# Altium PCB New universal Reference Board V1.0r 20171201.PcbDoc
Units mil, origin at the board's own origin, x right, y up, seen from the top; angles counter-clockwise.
Board outline 2509.05 x 980.62 mil, 4 copper layers (Top Layer, L2, L3, Bottom Layer), stack 24.2 mil thick; 38 components, 48 nets, 220 pads, 284 vias.

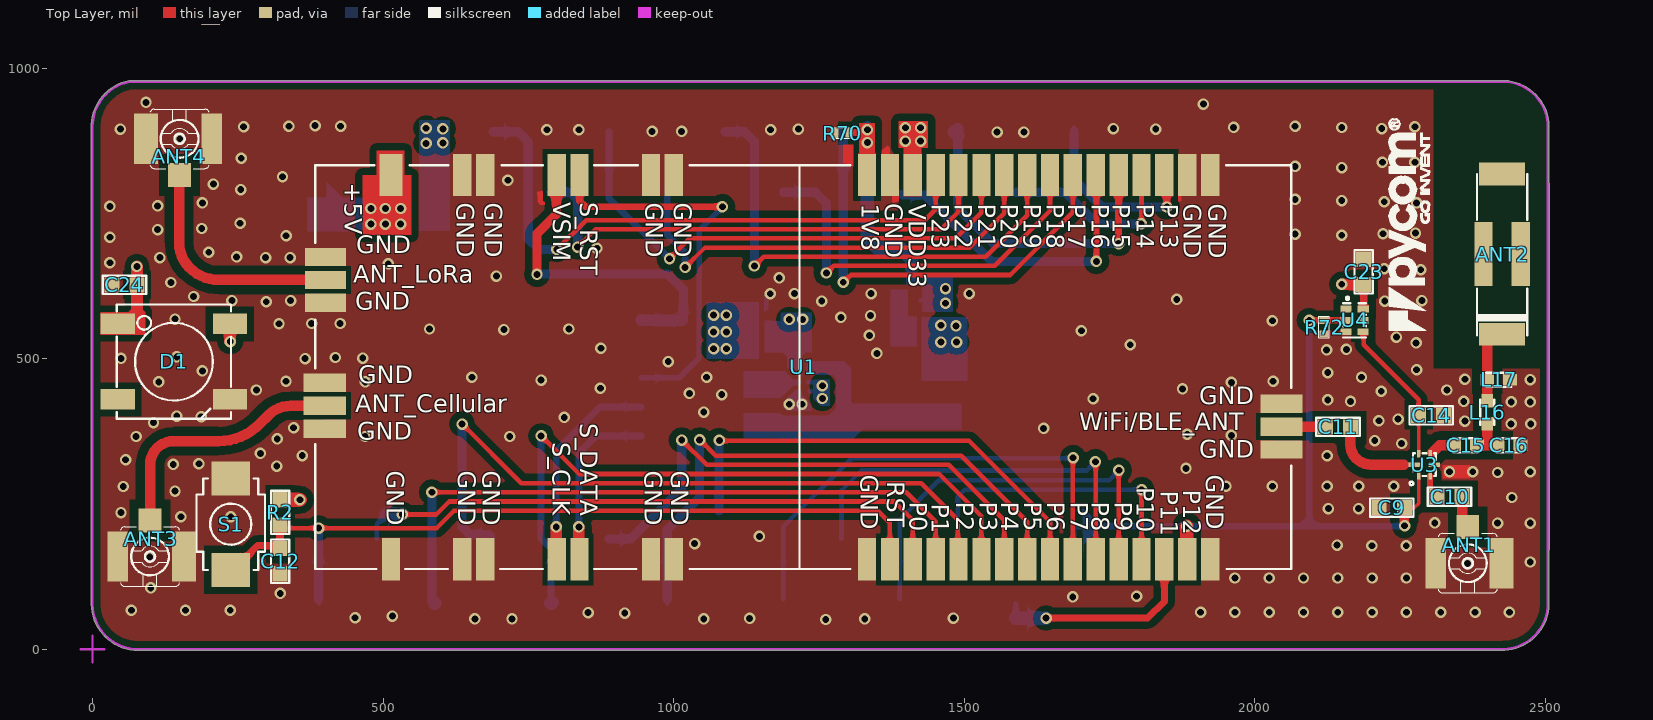
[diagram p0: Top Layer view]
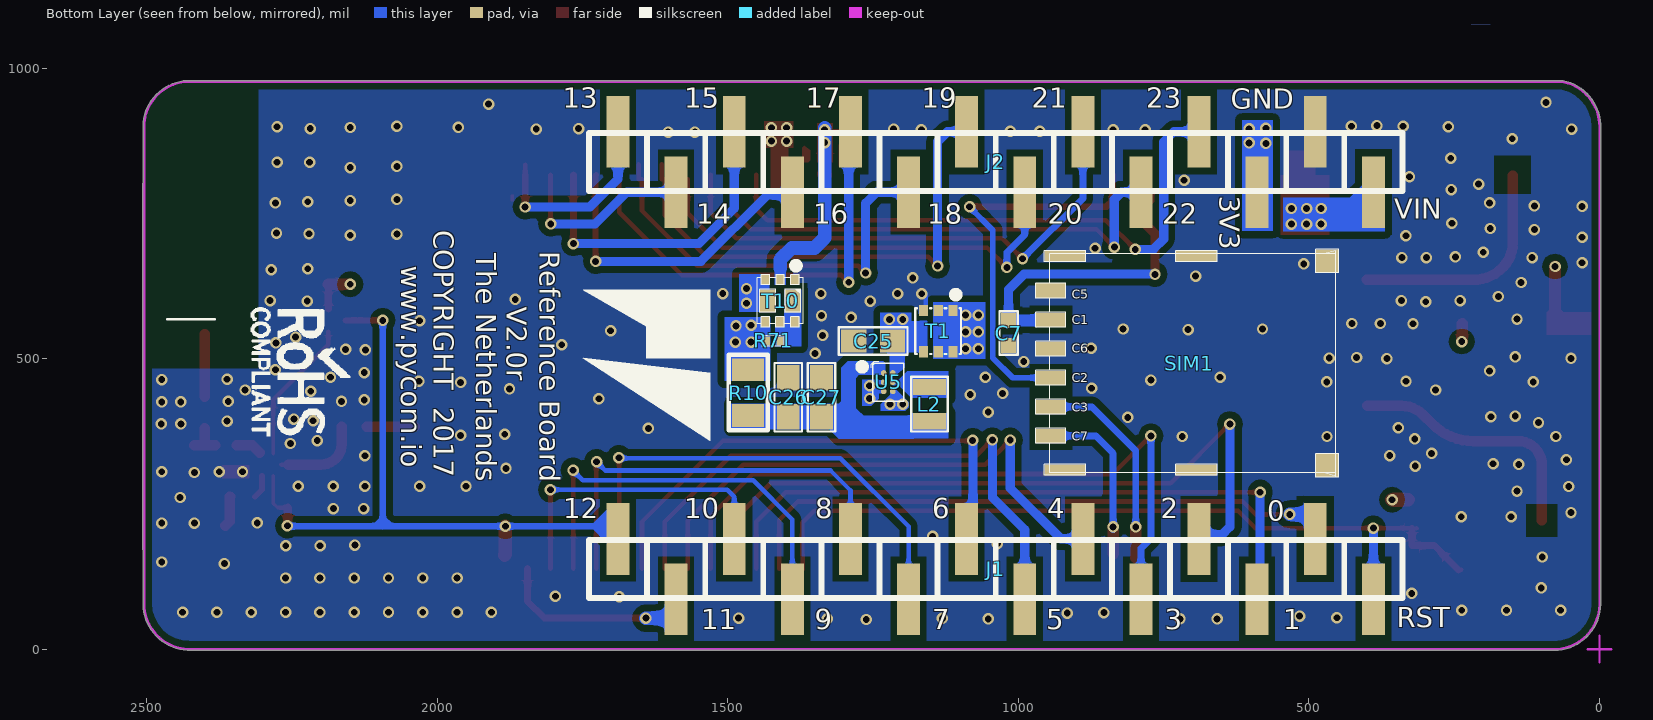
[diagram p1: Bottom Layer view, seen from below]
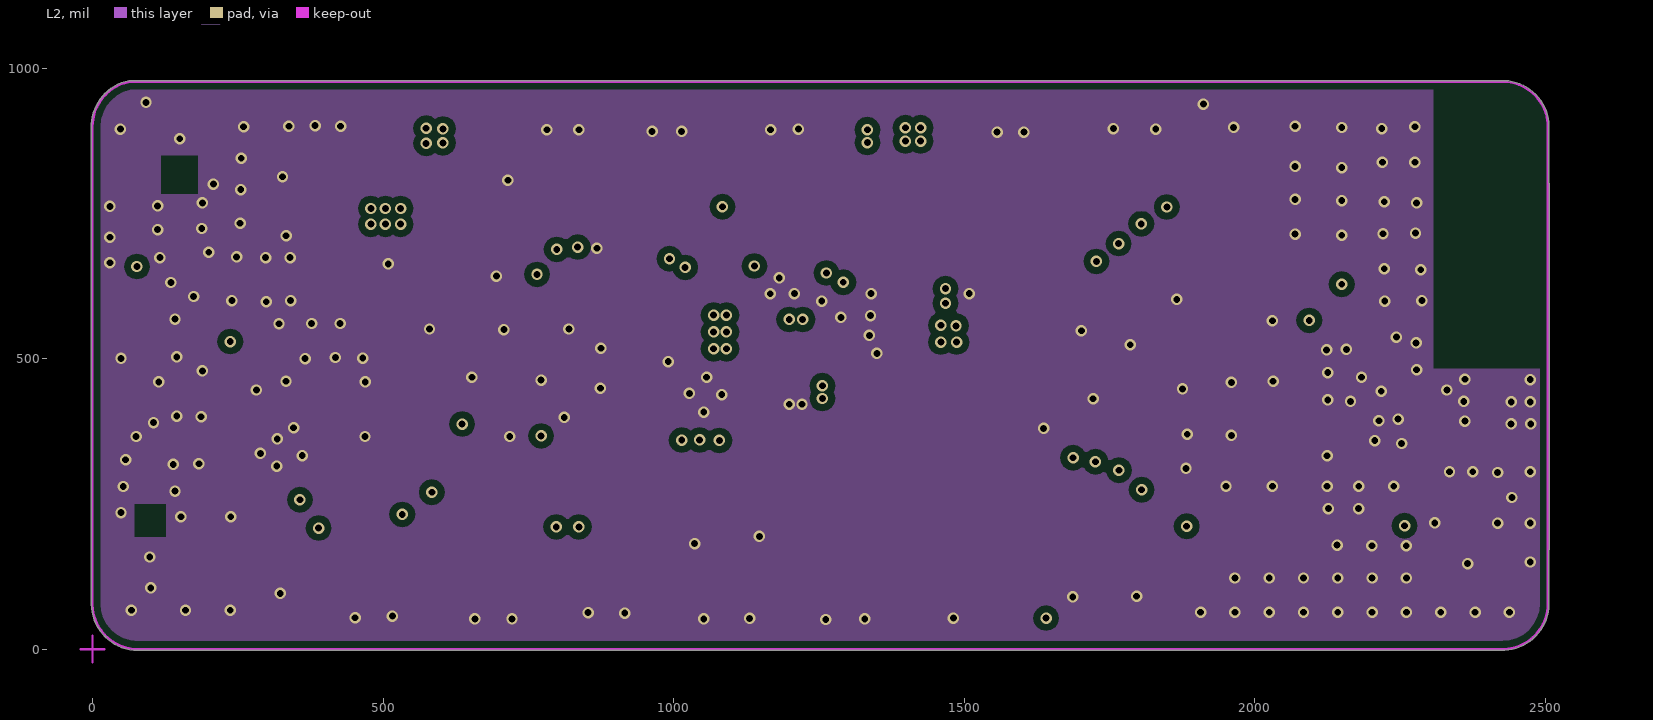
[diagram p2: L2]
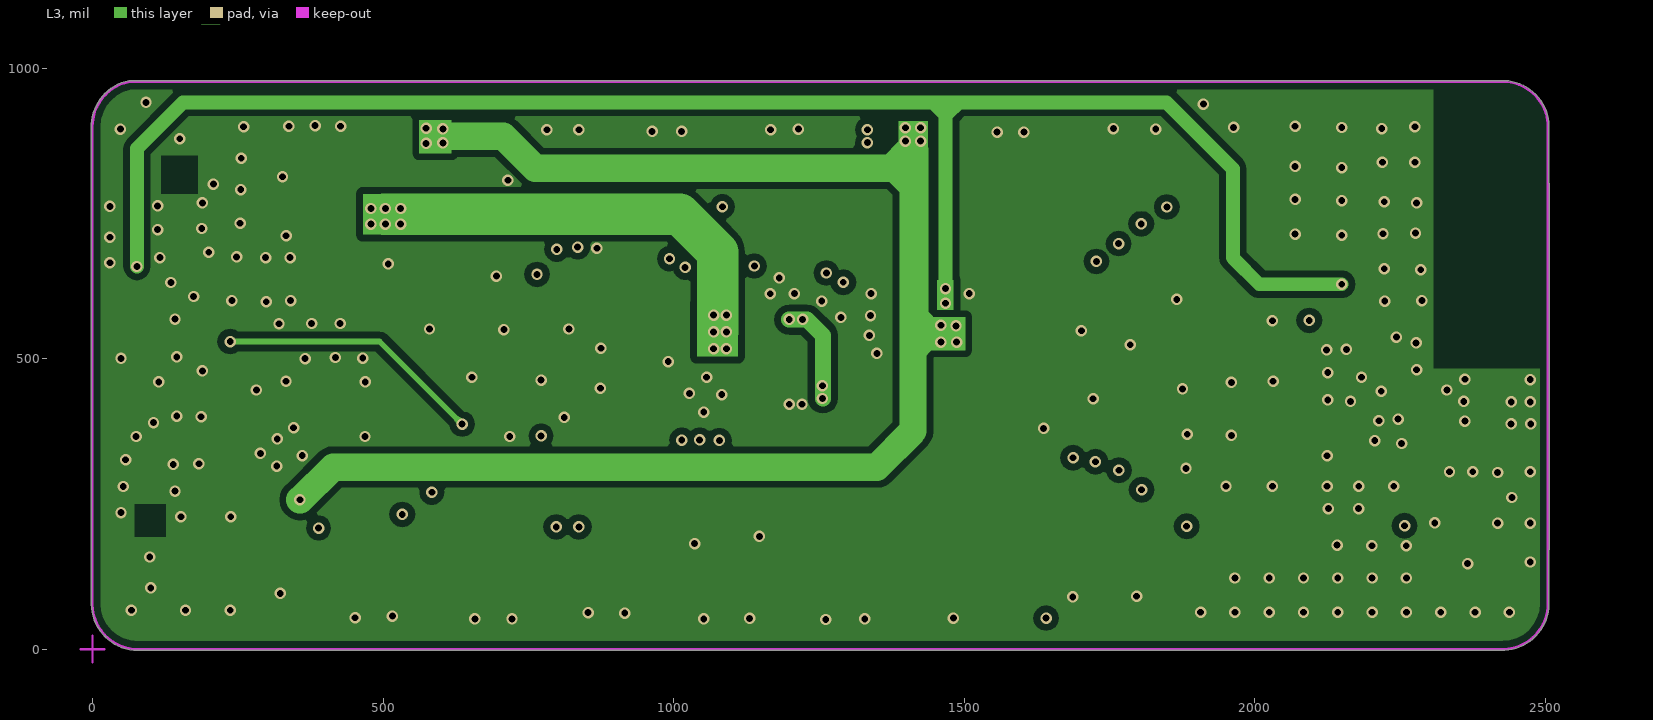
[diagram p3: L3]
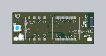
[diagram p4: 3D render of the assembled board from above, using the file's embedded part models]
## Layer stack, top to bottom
Top Solder: solder mask 0.4, Solder Resist, Dk 3.5
Top Layer: signal copper 0.7
Dielectric1: prepreg 5, FR-4, Dk 4.2
L2: signal copper 1.4
Dielectric2: core 10, FR-4, Dk 4.2
L3: signal copper 1.4
Dielectric3: prepreg 5, FR-4, Dk 4.2
Bottom Layer: signal copper 0.7
Bottom Solder: solder mask 0.4, Solder Resist, Dk 3.5

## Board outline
-1.98,170.5 cw(c-0.28,171.52) -2.27,171.52 -2.27,801.45 cw(c-0.28,801.45) -1.98,802.46 -1.98,898.44 cw(c78.74,899.16) -1.98,899.88 -1.98,902.45 cw(c0,902.45) -1.89,903.04 cw(c78.74,899.16) 62.75,978.29 cw(c63.61,976.5) 63.61,978.48 2425.1,978.48 cw(c2425.75,976.61) 2425.73,978.59 cw(c2426.46,897.87) 2429.32,978.55 cw(c2429.75,976.61) 2430.34,978.5 cw(c2426.46,897.87) 2506.66,907.02 cw(c2504.76,906.45) 2506.75,906.45 2506.75,801.82 cw(c2504.8,801.45) 2506.78,801.45 2506.78,171.52 cw(c2504.8,171.52) 2506.75,171.14 2506.75,79.41 ccw(c2426.03,78.69) 2506.75,79.42 2506.75,79.41 cw(c2426.03,78.69) 2506.75,78.69 cw(c2426.03,78.69) 2506.75,77.97 2506.75,77.45 cw(c2504.76,77.45) 2506.74,77.26 cw(c2426.03,78.69) 2430.25,-1.92 cw(c2429.75,0) 2429.75,-1.98 2428.77,-1.98 cw(c2426.03,78.69) 2427.05,-2.02 cw(c2427.03,-0.04) 2426.63,-1.98 71.66,-1.98 cw(c71.66,0) 71.13,-1.91 cw(c78.73,78.45) -1.98,77.43 cw(c0,77.45) -1.98,77.45

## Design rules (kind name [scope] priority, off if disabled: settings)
Clearance U1 [InComponent('U1')] p1: gap=7.87
Clearance U5 [InComponent('U5')] p2: gap=5
Clearance U3 [InComponent('U3')] p3: gap=5
Clearance LoRa [InPoly vs InNetClass('LoRa')] p4: gap=15
Clearance Polygon [InPolygon] p5: gap=11.81
Clearance [All] p6: gap=7.87
ComponentClearance [All] p1 off: gap=0 collisioncheckmode=3 verticalgap=0 showdistances=FALSE
FabricationTestPointUsage TestPointUsage [All] p1: valid=0 allowmultiple=FALSE
FabricationTestpoint Testpoint [(IsPad And (OnTopLayer Or OnBottomLayer))] p1: side=3 testpointundercomponent=TRUE minsize=40 maxsize=100 preferedsize=60 minholesize=0 maxholesize=40 preferedholesize=32 testpointgrid=1 allowsidetop=TRUE allowsidebottom=TRUE usegrid=TRUE gridtolerance=0.01
HoleToHoleClearance [All] p1: gap=11.81 allowstackedmicrovias=TRUE
PolygonConnect [All] p1: connectstyle=Direct reliefconductorwidth=10 reliefentries=4 polygonreliefangle="90 Angle" airgapwidth=10
RoutingVias [All] p1: holewidth=7.87 width=15.75 viastyle="Through Hole" minholewidth=5.91 minwidth=11.81 maxholewidth=59.06 maxwidth=78.74
SilkToSolderMaskClearance [IsPad] p1: minsilkscreentomaskgap=0 clearancetoexposedcopper=TRUE
SolderMaskExpansion [All] p1: expansion=4
Width [All] p1: maxlimit=118.11 minlimit=5.98 preferedwidth=10
25 further rules are at their usual default settings.

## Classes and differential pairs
component class "New universal Reference Board V1.0r 20171027": ANT1 ANT2 ANT3 ANT4 C7 C9 C10 C11 C12 C14 C15 C16 C23 C24 C25 C26 C27 D1 J1 J2 L2 L16 L17 R2 R10 R70 R71 R72 S1 SIM1 T1 T10 U1 U3 U4 U5
net class LoRa: NetANT1_1 NetANT2_1 NetANT3_1 NetANT4_1 NetC10_1 NetC11_1 NetC11_2 NetC15_1 NetC15_2

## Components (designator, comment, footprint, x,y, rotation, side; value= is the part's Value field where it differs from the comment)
ANT1 "ANT-SOCKET" ANT-SOCKET#1 2367.01,147.9 r0 top
ANT2 "ANT2450AT43B100" ANT-2450AT43B100 2426.06,679.79 r90 top locked
ANT3 "ANT-SOCKET" ANT-SOCKET#1 98.98,159.44 r0 top
ANT4 "ANT-SOCKET" ANT-SOCKET#2 148.43,847.43 r180 top
C7 "100nF_0402" 0402C#1 1017,544 r180 bottom
C9 "33pF_0402" 0402C#2 2236.12,243.44 r180 top
C10 "10pF_0402" 0402C#2 2335.51,262.47 r0 top
C11 "10pF_0402" 0402C#2 2143.4,382.45 r0 top
C12 "100nF_0402" 0402C#2 323.01,151.42 r270 top
C14 "33pF_0402" 0402C#2 2304.01,402.23 r0 top
C15 "10pF_0402" 0402CS 2363.07,350.66 r0 top
C16 "1.8pF_0402" 0402CS 2437.87,350.66 r180 top
C23 "100nF_0402" 0402C#2 2187.75,649.45 r90 top locked
C24 "100nF_0402" 0402C#2 54.96,627.05 r180 top
C25 "2.2UF_0603" 0603C 1250.12,530.44 r0 bottom
C26 "10uF_0603" 0603C 1396.12,433.58 r90 bottom locked
C27 "1uF_0603" 0603C 1339.12,433.58 r90 bottom
D1 "WS2812B" WS2812B 140.07,494.75 r0 top locked
J1 "CON14" SYMHC101-14GA40 1039.12,137.9 r0 bottom locked
J2 "CON14" SYMHC101-14GA40 1039.12,838.45 r180 bottom locked
L2 "0.47uH_0805" 0805L 1153.12,421.77 r270 bottom
L16 "2.2nH_0402" 0402CS 2400.47,407.74 r90 top
L17 "2.7pF_0402" 0402CS 2420.12,463.44 r180 top
R2 "20K_0402" 0402R 323.01,235.45 r270 top
R10 "0R_0805" 0805 1465.12,442.44 r270 bottom
R70 "220K_0201" 0201 1290,888 r0 top
R71 "220K_0201" 0201 1422.12,530.44 r0 bottom
R72 "220K_0201" 0201 2119.8,554.42 r90 top
S1 "TS-1185" SW-TS-1185 237.91,215.09 r90 top
SIM1 "693043020611_WUERTH" SIM_FiPy 706.33,492.23 r90 bottom locked
T1 "DMP2066UFDE" U-DFN2020-6 1138.12,547.44 r270 bottom
T10 "DMC1030UFDB" "U-DFN2020-6 TYPE B" 1410.12,599.44 r270 bottom
U1 "GPY_OEM" NEW_OEM_FootPrint 1223.12,485.4 r0 top locked
U3 "IC-SKY13350-385LF" MLPD-6 2292.2,317.59 r90 top locked
U4 "IC-SN74AUP1G04DRY" R-PUSON-N6(DRY) 2172.16,565.9 r180 top locked
U5 "IC-LM3281" DSBGA6(YFQ) 1224.12,459.44 r180 bottom
? "" LOGO4 2256.29,720.59 r90 top
? "" LOGO3 1614,491 r270 bottom

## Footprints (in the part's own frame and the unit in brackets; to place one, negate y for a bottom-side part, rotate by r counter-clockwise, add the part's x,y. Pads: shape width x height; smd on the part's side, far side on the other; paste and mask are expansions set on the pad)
0201 [mm]
  rect 0.3x0.4 smd: 1(-0.294,0.001) 2(0.293,0.002)
  silkscreen extent -0.47,-0.23 0.48,0.23
0402C#1 [mm]
  rect 0.66x0.66 smd mask+0.03: 1(0,0.55) 2(0,-0.55)
  silkscreen extent -0.4,-0.95 0.4,0.95
0402C#2 [mm]
  rect 0.66x0.66 smd mask+0.03: 1(-0.55,0) 2(0.55,0)
  silkscreen extent -0.95,-0.4 0.95,0.4, body extent -0.61,-0.25 0.59,0.26, height 0.51
0402CS [mm]
  rect 0.6x0.5 smd mask+0.05: 1(-0.5,0) 2(0.5,0)
  silkscreen extent -0.55,-0.31 0.55,0.31, body extent -0.61,-0.26 0.59,0.25, height 0.51
0402R [mm]
  rect 0.66x0.66 smd mask+0.03: 1(-0.55,0) 2(0.55,0)
  silkscreen extent -0.95,-0.4 0.95,0.4, body extent -0.5,-0.25 0.5,0.25, height 0.35
0603C [mm]
  rect 1.1x1 smd mask+0.05: 1(-0.85,0) 2(0.85,0.004)
  silkscreen extent -1.5,-0.6 1.5,0.6, body extent -0.78,-0.4 0.82,0.41, height 0.81
0805 [mm]
  rect 1x1.4 smd: 1(-0.975,0) 2(1.025,0)
  silkscreen extent -1.63,-0.85 1.67,0.85
0805L [mm]
  rect 0.7x1.45 smd mask+0.05: 1(-0.75,0) 2(0.75,0)
  silkscreen extent -1.2,-0.8 1.2,0.8, body extent -1,-0.64 1,0.64, height 1.27
ANT-2450AT43B100 [mm]
  rect 1x2 smd mask+0.05: 1(-3.5,0) 2(3.5,0)
  rect 2.8x0.8 smd mask+0.05: 3(0,-0.815) 4(0,0.815)
  silkscreen extent -3.55,-1.1 3.5,1.1, body extent -3.53,-1.14 3.55,1.13, height 2.1
ANT-SOCKET#1 [mm]
  rect 1x1.05 smd mask+0.05: 1(0,1.575)
  rect 0.9x2.2 smd mask+0.05: 2(-1.405,0)
  rect 1.05x2.2 smd mask+0.05: 3(1.475,0)
  silkscreen extent -1.29,-1.3 1.29,1.3, body extent -1.51,-1.32 1.49,1.53, height 1.27
ANT-SOCKET#2 [mm]
  rect 1x1.05 smd mask+0.05: 1(-0.035,0.788)
  rect 0.9x2.2 smd mask+0.05: 2(-1.44,-0.787)
  rect 1.05x2.2 smd mask+0.05: 3(1.44,-0.787)
  silkscreen extent -1.33,-2.09 1.26,0.51
DSBGA6(YFQ) [mm]
  round 0.25 smd mask+0.03: A1(-0.2,0.4) A2(0.2,0.4) B1(-0.2,0) B2(0.2,0) C1(-0.2,-0.4) C2(0.2,-0.4)
  silkscreen extent -0.74,-0.83 0.68,0.89, body extent -0.6,-0.74 0.6,0.74, height 0.4
LOGO3 [mil]
  silkscreen extent -127,-135 133,83
LOGO4 [mil]
  silkscreen extent -172,-46 193,25
MLPD-6 [mm]
  rect 0.33x0.15 smd mask+0.05: 1(-0.485,0.25) 2(-0.485,-0.25) 4(0.485,-0.25) 5(0.485,0.25)
  rect 0.2x0.51 smd mask+0.05: 3(0,-0.43) 6(0,0.43)
  silkscreen extent -0.9,-0.5 0.5,0.64, body extent -0.5,-0.51 0.51,0.51, height 0.5
NEW_OEM_FootPrint [mm]
  rect 1.85x0.8 smd mask+0.051: 24(20.911,-1.603) 25(20.911,-2.603) 26(20.911,-3.603) 27(-20.911,-0.689) 28(-20.911,-1.689) 29(-20.911,-2.689)
  rect 1.8x0.8 smd mask+0.05: 30(-20.886,4.811) 31(-20.886,3.811) 32(-20.886,2.811)
  rect 0.8x1.85 smd mask+0.051: L1(2.791,-8.401) L2(3.791,-8.401) L3(4.791,-8.401) L4(5.791,-8.401) L5(6.791,-8.401) L6(7.791,-8.401) L7(8.791,-8.401) L8(9.791,-8.401) L9(10.791,-8.401) L10(11.791,-8.401) L11(12.791,-8.401) L12(13.791,-8.401) L13(14.791,-8.401) L14(15.791,-8.401) L15(16.791,-8.401) L16(17.791,-8.401) L17(-5.654,-8.401) L18(-6.654,-8.401) L19(-9.776,-8.401) L20(-10.776,-8.401) L21(-13.898,-8.401) L22(-14.898,-8.401) L23(-18.02,-8.401) R1(2.791,8.402) R2(3.791,8.402) R3(4.791,8.402) R4(5.791,8.402) R5(6.791,8.402) R6(7.791,8.402) R7(8.791,8.402) R8(9.791,8.402) R9(10.791,8.402) R10(11.791,8.402) R11(12.791,8.402) R12(13.791,8.402) R13(14.791,8.402) R14(15.791,8.402) R15(16.791,8.402) R16(17.791,8.402) R17(-5.654,8.402) R18(-6.654,8.402) R19(-9.776,8.402) R20(-10.776,8.402) R21(-13.898,8.402) R22(-14.898,8.402)
  rect 1x1.85 smd mask+0.051: R23(-18.02,8.402)
  silkscreen extent -21.34,-8.83 21.34,8.83
R-PUSON-N6(DRY) [mm]
  rect 0.49x0.3 smd mask+0.05: 1(0.38,-0.5) 2(0.38,0) 3(0.38,0.5) 4(-0.37,0.5) 5(-0.37,0)
  rect 0.52x0.3 smd mask+0.05: 6(-0.38,-0.5)
  silkscreen extent -0.5,-1.03 0.5,0.75, body extent -0.5,-0.75 0.5,0.75, height 0.6
SIM_FiPy [mm]
  rect 0.48x1.8 smd mask+0.025: 0(-4.665,-0.325) 0(-4.665,5.425) 0(4.665,-0.325) 0(4.665,5.425)
  rect 1.03x1 smd mask+0.025: 0(-4.47,-6.045) 0(4.46,-6.045)
  rect 0.65x1.3 smd mask+0.025: C1(1.9,6.045) C2(-0.64,6.045) C3(-1.91,6.045) C5(3.17,6.045) C6(0.63,6.045) C7(-3.18,6.045)
  silkscreen extent -4.98,-6.54 4.98,6.7
SW-TS-1185 [mm]
  rect 1.5x1.7 smd: 1(-2,0) 2(2,0)
  silkscreen extent -2,-1.5 2,1.5, body extent -2.5,-1.5 2.5,1.52, height 2
SYMHC101-14GA40 [mm]
  rect 1x3.14 smd: 1(-16.51,1.32) 2(-13.97,-1.32) 3(-11.43,1.32) 4(-8.89,-1.32) 5(-6.35,1.32) 6(-3.81,-1.32) 7(-1.27,1.32) 8(1.27,-1.32) 9(3.81,1.32) 10(6.35,-1.32) 11(8.89,1.32) 12(11.43,-1.32) 13(13.97,1.32) 14(16.51,-1.32)
  silkscreen extent -17.78,-1.27 17.78,1.27
U-DFN2020-6 [mm]
  rect 0.5x0.4 smd mask+0.05: D0(-0.9,0.65) D1(-0.9,0) D2(0.9,0) D3(0.9,0.65)
  rect 0.5x0.4 smd mask+0.025: G(-0.9,-0.65) S(0.9,-0.65)
  Top Layer region: -0.45,-0.5 0.45,-0.5 0.45,-0.8 -0.45,-0.8
  Top Layer region: -0.8,0.85 0.8,0.85 0.8,-0.2 -0.8,-0.2
  silkscreen extent -1,-1 1,1, body extent -1,-1 1.02,1, height 0.63
"U-DFN2020-6 TYPE B" [mm]
  rect 1x0.7 smd mask+0.051: D1(0,0.55) D2(0,-0.55)
  rect 0.45x0.37 smd mask+0.051: D1(0.925,0.65) D2(-0.925,-0.65) G1(-0.925,0) G2(0.925,0) S1(-0.925,0.65) S2(0.925,-0.65)
  silkscreen extent -1.15,-1 1.15,1
WS2812B [mm]
  rect 1.5x0.9 smd mask+0.05: 1(-2.45,1.65) 2(-2.45,-1.65) 3(2.45,-1.65) 4(2.45,1.65)
  silkscreen extent -2.5,-2.5 2.5,2.5, body extent -2.6,-2.47 2.6,2.53, height 2.01

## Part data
C7: library part CAP-2, "SMD  Capacitor 0201"
C9 C14: library part CC0402/33PF/J%
C10 C11: library part CC0402/10PF/D%
C12 C23 C24: library part CC0402/100NF/K%16V
C15: library part CC0402/10PF/D%_S
C16 L17: library part CC0402/0,5pF/+/-0.1pF_S
C25 C26: library part CC0603/10UF/10V/K%
C27: library part CC0603/1UF/K%/10V
D1: library part DIO-WS2812B
L2: library part IND0805/0.47uH/20%
L16: library part IND0402/6.8nH/+/-0.1nH_S
R2 R10: library part RC0402/100K/F%
R70 R71 R72: library part RC0402/20K/F%
S1: library part SW-TS-1185
SIM1: library part "SIM CARD"
T1: library part FET-P-DMP2066UFDE
U1: library part LOPYOEM_Mother_Board, "LOPYOEM_Mother_Board"

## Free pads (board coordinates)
  round 35 on Bottom Overlay: 2(389.12,838.45) 3(489.12,838.45) 4(589.12,838.45) 5(689.12,838.45) 6(789.12,838.45) 7(889.12,838.45) 8(989.12,838.45) 9(1089.12,838.45) 10(1189.12,838.45) 11(1289.12,838.45) 12(1389.12,838.45) 13(1489.12,838.45) 14(1589.12,838.45) 15(1689.12,838.45) 16(389.12,136.48) 17(489.12,136.48) 18(589.12,136.48) 19(689.12,136.48) 20(789.12,136.48) 21(889.12,136.48) 22(989.12,136.48) 23(1089.12,136.48) 24(1189.12,136.48) 25(1289.12,136.48) 26(1389.12,136.29) 27(1489.12,136.48) 28(1589.12,136.48) 29(1689.12,136.48)
  round 23.62 on Top Overlay: 30(2487.14,551.25) 35(88.12,560.96)
  round 19.68 on Top Overlay: 33(20.32,593.03)
  round 11.81 on Top Overlay: 34(2270.12,285.44)

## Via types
v1: diameter 19.68, hole 11.81, Top Layer to Bottom Layer, tented both sides, 284 vias

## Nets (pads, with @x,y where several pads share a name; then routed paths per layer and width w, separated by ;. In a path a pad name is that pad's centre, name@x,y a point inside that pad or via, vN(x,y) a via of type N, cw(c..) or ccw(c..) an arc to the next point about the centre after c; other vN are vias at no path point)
+5V: J2.14 T1.D0 T1.D1 T1.D2 T1.D3 U1.R23 | length 737.7
  L3 w70.87: 502.12,748.44 1010.56,748.44 1076,683 v1@1076,546.32
  other v1: 1069,517 1091,517 1069,546 1091,546 1069,575 1091,575 479.12,731.44 504.12,731.44 530.12,731.44 479.12,758.44 504.12,758.44 530.12,758.44
DAC1(GP9): J2.10 U1.R5 | length 877.1
  Top Layer w7.87: v1(835,692) 865.69,722.69 1460.37,722.69 1490.48,752.8 U1.R5
  Bottom Layer w15.75: J2.10 822.52,786.48 835,774 v1(835,692)
DAC2(GP8): J2.9 U1.R6 | length 896.1
  Top Layer w7.87: v1(993,672) 1027.94,706.94 1485.62,706.94 1529.85,751.17 U1.R6
  Bottom Layer w11.81: J2.9 889.12,775.88 v1(993,672)
GND: ANT1.2 ANT1.3 ANT3.2 ANT3.3 ANT4.2 ANT4.3 C7.2 C9.2 C12.2 C14.2 C16.1 C23.2 C24.2 C25.2 C26.2 C27.2 D1.3 J2.13 L17.1 R70.1 R72.1 S1.2 SIM1.0 SIM1.C5 SIM1.C6 T1.G T10.S1 U1.24 U1.26 U1.27 U1.29 U1.30 U1.32 U1.L1 U1.L16 U1.L17 U1.L18 U1.L21 U1.L22 U1.L23 U1.R2 U1.R15 U1.R16 U1.R17 U1.R18 U1.R21 U1.R22 U3.3 U4.3 U5.C2
  other v1: 1262,51 658,52 722,52 1052,52 1131,53 1329,52 1481.57,53.42 452,54 516,57 853,63 916,62 1907.05,63.44 1966.11,63.44 2025.16,63.44 2084.22,63.44 2143.27,63.44 2202.33,63.44 2261.38,63.44 2320.44,63.44 2379.49,63.44 2438.55,63.44 67,67 160,67 237,67 1687,90 1797,91 323,96 100.12,105.44 1966.11,122.49 2025.16,122.49 2084.22,122.49 2143.27,122.49 2202.33,122.49 2261.38,122.49 2366.61,147.11 2474.5,150 98.58,158.65 2142,179 2202,178 2261,178 1036.29,181.79 1147.66,194 2418.37,216.9 2474.5,216.9 2310.12,217.44 152,228 238,228 49,235 2127,242 2179,242 2443,261 142,272 53,280 1950.85,280.42 2030.75,280.42 2124.89,280.42 2179.39,280.42 2239.66,280.42 2418.37,304.04 2335.51,305.38 2375.58,305.38 2474.5,305.38 1882,311 317,315 139,318 183,319 57,326 361,333 2124.89,332.78 289,337 2253,354 2206.75,358.9 318,362 75,366 469,366 718,366 1960,368 1884.17,369.9 346,381 1637,380 2441.62,387.78 2475.37,387.78 105,390 2214,393 2362.12,392.44 2247,396 812,399 145,401 187,400 1052,408 1199.12,421.44 1221.12,421.44 2441.81,425.45 2474.5,425.45 2165.12,426.44 2360.12,426.44 2126,429 1722,431 1083,438 1027.23,440.21 2218,444 282,446 2331,446 874,449 1876,448 1960,459 114,460 333,461 469.32,460.03 2032,461 772,463 2362.12,464.44 2474.5,464.05 653,468 1057,468 2184,468 2126,476 189,479 2279,481 991,495 48.96,500.44 366,500 465,501 145,503 418,502 1350,509 2124,515 2158,516 875,518 1786,524 2278,527 2244,537 1337,540 1702,548 580,551 708,550 820,551 321,560 377.12,560.44 426.12,560.44 2030.75,565.22 142,568 1288,571 1339,574 299,598 1255,599 2224,599 240,600 341,600 2288,600 1866,602 174,607 1166.41,611.7 1208,612 1340,612 1509,612 135,631 1182,639 695,642 2286,653 2223.18,654.74 509,663 29.96,665.05 116,674 248,675 298,674 340,674 200,683 868,690 29.96,709 333.12,711.44 2149.96,712.27 2069.75,714.27 2221,715 2277,716 112,722 188,724 254,733 29.96,762 112,763 189,768 2279,768 2223.18,770.05 2149.96,772.05 2069.75,774.05 255,791 208.12,800.44 715,807 327,813 2149.96,828.82 2069.75,830.82 2220,838 2276,838 256,845 150.12,878.44 963,891 1014,891 1557,890 1603,890 48,895 782,894 837,894 1167,894 1215,895 1830,895 1757,896 2219,896 2149.96,897.88 260,899 1964,898 2276,899 2069.75,899.88 338,900 383,901 427,900 1912,938 92,941
GPI2(2): J1.10 U1.L11 | length 732.4
  Top Layer w7.87: v1(1726.12,322.44) 1726.7,321.85 U1.L11 U1.L11@1726.7,138.51
  Bottom Layer w7.87: J1.10 1289.12,273.12 1323.44,307.44 1711.12,307.44 v1(1726.12,322.44) 1726.12,326.44 1725.62,326.94 v1@1723.62,324.94
GPI36: J2.1 U1.R14 | length 346.1
  Top Layer w7.87: U1.R14@1848.81,808.69 U1.R14@1848.81,833.37
  Top Layer w11.81: v1@1848.81,761.74 U1.R14@1848.81,815.17
  Bottom Layer w7.87: J2.1 J2.1@1689.12,897.51
  Bottom Layer w15.75: J2.1 1689.12,809.44 1737.56,761 v1(1849,761)
GPI37: J2.2 U1.R13 | length 322.8
  Top Layer w7.87: v1(1805,732) 1805.44,732.44 U1.R13
  Bottom Layer w15.75: J2.2 1674.07,786.48 1728.56,732 v1(1805,732)
GPI38: J2.3 U1.R12 | length 568.1
  Top Layer w11.81: v1(1766,698) 1766.07,698.07 U1.R12
  Bottom Layer w10: J2.3@1489.12,883.94 J2.3
  Bottom Layer w15.75: J2.3@1489.12,883.94 1489.12,758.88 1550,698 v1(1766,698)
  Bottom Layer w19.68: J2.3@1485.12,891.45 J2.3@1489.12,895.45
  Bottom Layer w23.62: J2.3@1485.12,891.45 1483.36,889.7 J2.3@1489.12,883.94
GPI39: J2.4 U1.R11 | length 537.2
  Top Layer w10: U1.R11 1727.74,815.13 v1(1727.74,667.38)
  Bottom Layer w10: J2.4 J2.4@1394.17,781.44
  Bottom Layer w15.75: J2.4@1394.17,781.44 1432.56,781.44 1546.62,667.38 v1(1727.74,667.38)
GPIO00: D1.4 J1.4 U1.L5 | length 1711.6
  Top Layer w7.87: v1(636.12,387.44) 737.88,285.68 1426.33,285.68 1489.12,222.89 U1.L5@1489.12,173.45
  Top Layer w10: v1@236.53,530.03 v1(237.12,529.44)
  Top Layer w19.68: v1@236.53,530.03 D1.4
  L3 w10: v1(237.12,529.44) 494.12,529.44 v1(636.12,387.44)
  Bottom Layer w7.87: J1.4@682.03,196.96 J1.4 689.12,196.96 J1.4@682.03,196.96
  Bottom Layer w15.75: v1(636.12,387.44) 636.12,210.44 649.6,196.96 J1.4@682.03,196.96
GPIO02(GPIO03): J1.2 U1.L3 | length 1061.1
  Top Layer w7.87: v1(533.12,231.96) 533.29,231.78 591.47,231.78 613.87,254.19 1379.83,254.19 1411.74,222.27 U1.L3@1411.74,138.51
  Bottom Layer w7.87: J1.2 489.12,214.95 J1.2@506.13,231.96
  Bottom Layer w23.62: J1.2@506.13,231.96 v1(533.12,231.96)
GPIO04: J1.5 U1.L6 | length 1205.2
  Top Layer w7.87: v1(772,367) 837.57,301.43 1457.63,301.43 1529.85,229.21 U1.L6@1529.85,138.51
  Bottom Layer w7.87: v1(772,367) 773.86,367 v1@775,365.86 ; J1.5@790.96,80.69 J1.5@790.96,85.93
  Bottom Layer w11.81: v1@775,365.86 772,362.86 772,190.77 789.12,173.65 J1.5
  Bottom Layer w23.62: J1.5@789.12,78.85 J1.5@790.96,80.69
GPIO12(18): J1.11 U1.L12 | length 720.3
  Top Layer w7.87: U1.L12@1766.07,138.51 v1@1766.07,308.44
  Bottom Layer w7.87: J1.11 1389.12,223.12 1456.44,290.44 1750.12,290.44 1766.62,306.94 v1(1766.62,307.94)
GPIO13(19): J1.12 U1.L13 | length 536
  Top Layer w7.87: U1.L13@1805.44,138.51 U1.L13 v1@1805.44,280.44
  Bottom Layer w7.87: J1.12 1489.12,262.44 1501.12,274.44 v1(1805.62,274.44)
GPIO14(14): J2.11 U1.R4 | length 1031.2
  Top Layer w7.87: v1(799,688) 849.44,738.44 1432.12,738.44 1451.11,757.43 U1.R4
  Bottom Layer w15.75: J2.11 732.58,890.42 750,873 750,706 768,688 v1(799,688)
GPIO15: J1.6 U1.L7 | length 939.5
  Top Layer w7.87: v1(1014.08,359.82) 1014.27,359.82 1056.91,317.18 1473.99,317.18 1569.22,221.94 U1.L7@1569.22,138.51
  Bottom Layer w15.75: J1.6 926.87,189.87 1014.08,277.08 v1(1014.08,359.82)
GPIO21(6): C9.1 J1.14 R72.2 U1.L15 U3.1 U4.2 | length 1168.1
  Top Layer w6: v1@2257.77,212.78 v1(2258.12,212.44) ; C9.1 2275.12,243.44 2282.36,250.68 U3.1
  Top Layer w10: v1@2091.8,565.9 U4.2@2158.18,565.9
  Top Layer w15: v1@2257.77,212.78 C9.1
  Top Layer w23.62: v1(1883.12,211.44) 1883.12,163.18 U1.L15@1884.18,162.11
  Bottom Layer w7.87: J1.14 J1.14@1689.12,211.44 ; v1@2257.12,211.44 v1(2258.12,212.44)
  Bottom Layer w11.81: J1.14@1689.12,211.44 v1@2257.12,211.44 ; 2094.12,211.44 v1(2094.12,565.9)
GPIO22(11): J1.13 U1.L14 | length 349.4
  Top Layer w11.81: v1(1641.17,53.42) 1816.1,53.42 1844.81,82.13 U1.L14@1844.81,138.51
  Bottom Layer w7.87: J1.13@1589.12,53.42 J1.13@1589.12,78.85
  Bottom Layer w23.62: J1.13@1589.12,53.42 v1(1641.17,53.42)
GPIO32(3): J2.7 U1.R8 | length 864.3
  Top Layer w7.87: v1(1139.12,659.44) 1155.13,675.45 1537.38,675.45 1608.59,746.66 U1.R8@1608.59,808.69 ; U1.R8@1613.8,808.69 U1.R8@1613.8,834.29
  Bottom Layer w15.75: J2.7 1122.13,890.42 1139.12,873.44 v1(1139.12,659.44)
GPIO33(12): J2.8 U1.R7 | length 814
  Top Layer w7.87: v1(1020,657) 1054.19,691.19 1509.88,691.19 1569.22,750.54 U1.R7@1569.22,808.69 ; U1.R7@1574.43,808.69 U1.R7@1574.43,834.29
  Bottom Layer w11.81: J2.8 989.12,713.88 1020,683 v1(1020,657)
LORA_CLK: J1.7 U1.L8 | length 1007.4
  Top Layer w7.87: v1(1044.92,360.2) 1045.5,360.2 1072.78,332.93 1495.09,332.93 1608.59,219.42 U1.L8@1608.59,138.51
  Bottom Layer w7.87: J1.7@989.12,78.85 J1.7
  Bottom Layer w15.75: J1.7 989.12,205.4 1044.92,261.2 v1(1044.92,360.2)
LORA_MISO: J1.9 U1.L10 | length 863.6
  Top Layer w7.87: U1.L10@1687.33,138.51 U1.L10 v1@1687.33,329.44
  Bottom Layer w7.87: J1.9 1189.12,211.12 1306.44,328.44 1686.62,328.44 v1(1687.62,329.44)
LORA_MOSI: J1.8 U1.L9 | length 831.3
  Top Layer w7.87: v1(1078.83,359.23) 1079.63,358.44 1508.57,358.44 1647.96,219.05 U1.L9@1647.96,138.51
  Bottom Layer w7.87: v1@1078.26,356.34 v1@1081.85,359.94
  Bottom Layer w15.75: J1.8@1078.26,237.9 v1@1078.26,356.34
NetANT1_1: ANT1.1 C10.2 | length 53.5
  Top Layer w18: C10.2@2357.42,262.21 2357.42,219.89 ANT1.1@2365.04,212.27
  Top Layer w18.6: C10.2 C10.2@2357.42,262.21
NetANT2_1: ANT2.1 L16.2 L17.2 | length 107.7
  Top Layer w18: L16.2@2400.47,434.32 ANT2.1@2400.47,542
NetANT3_1: ANT3.1 U1.28 | length 438.4
  Top Layer w18: ANT3.1 98.98,316.97 cw(c140.03,316.97) 111,346 cw(c139.97,317.03) 139.97,358 216.58,358 ccw(c216.58,458) 287.29,387.29 303,403 cw(c341.39,364.61) 341.39,418.9 U1.28
NetANT4_1: ANT4.1 U1.31 | length 402.2
  Top Layer w18: ANT4.1@149.12,814.44 149.12,699.89 ccw(c210.57,699.89) 167.12,656.44 ccw(c217.82,707.14) 217.82,635.44 U1.31
NetC10_1: C10.1 U3.2 | length 40.9
  Top Layer w10: U3.2 2302.04,274.28 C10.1
NetC11_1: C11.1 U1.25 | length 83
  Top Layer w11.81: C11.1@2121.3,382.9 C11.1
  Top Layer w18: U1.25@2038.91,382.9 C11.1@2121.3,382.9
NetC11_2: C11.2 U3.6 | length 153.3
  Top Layer w7.87: 2256.77,317.59 U3.6@2268.58,317.59
  Top Layer w18: C11.2 2165.06,351.85 ccw(c2198.15,351.85) 2174.75,328.45 ccw(c2200.98,354.69) 2200.98,317.59 2256.77,317.59
NetC14_1: C14.1 U3.5 U4.4 | length 248.7
  Top Layer w6: U3.5 C14.1
  Top Layer w7.87: U4.4@2187.71,546.22 2187.71,523.84 2282.36,429.19 C14.1
NetC15_1: C15.1 U3.4 | length 45.9
  Top Layer w6: U3.4 U3.4@2302.04,338
  Top Layer w18: 2306,338 2318.66,350.66 C15.1 ; C15.1@2343.38,351.15 C15.1@2345.35,351.15
NetC15_2: C15.2 C16.2 L16.1 | length 65.4
  Top Layer w18: C15.2 2400.47,350.66 ; L16.1@2400.47,380.58 2400.47,350.66 ; C16.2 2400.47,350.66
NetC26_1: C26.1 C27.1 L2.2 R10.2 U5.A1 | length 443.4
  Bottom Layer w7.87: U5.A1@1235.39,475.44 1284.12,475.44 ; 1429.12,392.24 1448.28,392.24 R10.2@1458.12,402.08
  Bottom Layer w19.68: 1284.12,475.44 1289.12,470.44 1289.12,392.24
  Bottom Layer w25: L2.2@1155.92,389.44 1283.12,389.44
  Bottom Layer w27.56: L2.2 L2.2@1155.92,389.44 ; 1283.12,389.44 1285.92,392.24 1289.12,392.24 ; 1291.12,392.24 1429.12,392.24
NetR71_1: R71.1 T10.D1 T10.G2 | length 124.4
  Bottom Layer w7.87: T10.D1@1388.47,599.44 1384.53,595.5 1384.53,563.02 1384.53,538.03 1391.72,530.83 R71.1@1410.12,530.83 ; T10.G2 R71.1@1410.12,530.83 ; R71.1 R71.1@1410.12,530.83
PU(NRESET): C12.1 J1.1 R2.2 S1.1 U1.L2 | length 1420.4
  Top Layer w7.87: S1.1 S1.1@242.5,136.35 ; R2.2@314.57,208.41 321.83,207.51 322.23,207.46 R2.2@322.61,207.41 ; R2.2@322.08,208.41 v1(389.12,208.41) 592.1,208.41 622.12,238.44 1351.57,238.44 1372.37,217.64 U1.L2@1372.37,162.11 ; U1.L2@1371.16,137.58 U1.L2@1371.16,162.11
  Top Layer w11.81: S1.1@242.5,136.35 284.26,178.11 322.61,178.11 R2.2@322.61,207.41
  Bottom Layer w7.87: J1.1@389.12,78.85 J1.1
  Bottom Layer w15.75: J1.1 v1(389.12,208.41)
RF_POWER: C23.1 C24.1 D1.1 T10.D2 U4.6 | length 3057
  Top Layer w11.81: U4.6@2187.71,585.59 C23.1 C23.1
  Top Layer w19.68: v1(2149.96,628.05) 2187.5,628.05 C23.1
  Top Layer w20: D1.1 72.71,559.71 76.49,563.49 v1(76.49,658.58)
  L3 w23.62: v1(76.49,658.58) 76.49,861.81 155.62,940.94 1848.42,940.94 1962.75,826.6 1962.75,673.45 2008.15,628.05 v1(2149.96,628.05) ; v1(1468.12,620.44) 1468.12,933.44
  Bottom Layer w7.87: T10.D2@1425.77,599.44 T10.D2@1429.71,603.37
  other v1: 1468.12,595.44
SIM_CLK: SIM1.C3 U1.L20 | length 369.6
  Top Layer w11.81: v1(798.12,210.44) 798.12,203.31 v1@798.88,202.55
  Top Layer w19.68: U1.L20@798.12,157.52 v1(798.12,210.44)
  Bottom Layer w11.81: v1(798.12,210.44) 798.12,341.44 873.71,417.03 SIM1.C3
SIM_DATA: SIM1.C7 U1.L19 | length 303
  Top Layer w11.81: v1@837.12,205.44 838.25,204.31 v1@838.25,201.35
  Top Layer w19.68: U1.L19@837.12,163.72 v1(837.12,210.44)
  Bottom Layer w11.81: v1@837.12,205.44 837.12,336.87 838.25,338 837.97,338.29 866.71,367.03 SIM1.C7
SIM_RESET: SIM1.C2 U1.R19 | length 685.6
  Top Layer w11.81: U1.R19 838.25,771.31 848.12,761.44 v1(1084.12,761.44)
  Bottom Layer w10: SIM1.C2 1010.03,467.03 1044.13,501.13 1044.13,721.13 1084.12,761.12 v1(1084.12,761.44)
SW: L2.1 U5.B2 | length 60.6
  Bottom Layer w6: L2.1@1153.12,458.96 1153.59,459.44 1202.42,459.44
  Bottom Layer w7.87: 1205.23,459.63 1216.06,459.63 U5.B2
U0TXD(GPIO01): J1.3 U1.L4 | length 1161.4
  Top Layer w7.87: v1@584.98,269.3 585.62,269.93 1400.36,269.93 1451.11,219.18 U1.L4@1451.11,138.51
  Bottom Layer w7.87: J1.3@584.12,83.85 J1.3@588.96,79
  Bottom Layer w15.75: v1(584,270) 584,83.97 J1.3@584.12,83.85
  Bottom Layer w23.62: J1.3@588.96,79 J1.3@589.12,78.85
VDD1V8: R70.2 T10.G1 U1.R1 | length 422.6
  Top Layer w10: v1@1332.62,893.94 1332.62,896.07 v1@1339.69,889
  Top Layer w11.81: R70.2@1302.12,889 v1@1339.69,889
  Top Layer w23.62: U1.R1 1335.12,818.29 1333.62,819.79 v1(1333.62,871.94)
  Bottom Layer w7.87: T10.G1 1410.12,655.44
  Bottom Layer w23.62: v1@1333.62,896.94 v1(1333.62,871.94) 1333.62,707.94 1351.12,690.44 1390.12,690.44 1410.12,670.44 1410.12,655.44
  other v1: 1333.62,893.94
VDD5: C25.1 T1.S U5.A2 U5.B1 U5.C1 | length 400.4
  L3 w27.56: v1@1199.12,567 1230,567 1257.12,539.88 v1@1257.12,431.44
  Bottom Layer w7.87: 1165.12,555.44 1165.12,518.41 1164.71,518 1204.22,518 C25.1@1216.24,530.03 ; U5.A2@1216.24,478.56 C25.1@1216.24,530.03 ; C25.1 C25.1@1216.24,530.03 ; U5.B1 1252.12,459.44 1255.12,456.44 v1@1255.12,444.44 ; U5.C1@1234.24,443.69 1254.37,443.69 v1@1255.12,444.44 ; v1@1255.12,425.44 v1@1255.12,444.44
  other v1: 1256.12,431.44 1256.12,453.44 1199.12,567.44 1222.12,567.44
VDD33: J2.12 R2.1 R10.1 R71.2 T10.S2 U1.R3 | length 2622.2
  Top Layer w23.62: R2.1@329.61,257.11 329.66,257.05 v1(356.96,257.05)
  L3 w11.81: 1415.12,463.44 1415.12,542.44 ; v1(1460.12,528.44) 1474.12,542.44
  L3 w47.24: v1(356.96,257.05) 357.73,257.05 414.12,313.44 1350.12,313.44 1412.12,375.44 1412.12,881.44 ; 608.12,882.44 707.12,882.44 761.89,827.66 1411.84,827.66 1412.12,827.94 ; 1415.12,542.44 1474.12,542.44
  other v1: 1487.12,528.44 1486.12,556.44 1460.12,557.44 574.12,870.44 603.12,871.44 1399.12,874.44 1425.12,874.44 603.12,895.44 574.12,896.44 1399.12,897.44 1425.12,897.44
VDET-1(GP30): J2.6 U1.R9 | length 710.8
  Top Layer w7.87: v1(1263.12,647.44) 1275.38,659.7 1553.09,659.7 1647.96,754.57 U1.R9@1647.96,808.69 ; U1.R9@1653.17,808.69 U1.R9@1653.17,834.29
  Bottom Layer w15.75: J2.6 1244.07,786.48 1263.12,767.44 v1(1263.12,647.44)
VDET-2(GP31): J2.5 U1.R10 | length 1046.8
  Top Layer w7.87: v1(1292.12,631.44) 1304.63,643.95 1579.55,643.95 1687.33,751.73 U1.R10@1687.33,808.69 ; U1.R10@1692.54,808.69 U1.R10@1692.54,834.29
  Bottom Layer w7.87: v1@1289.12,631.44 J2.5
  Bottom Layer w15.75: J2.5 1292.12,887.42 v1(1292.12,631.44)
VSIM(SIM_VCC): C7.1 SIM1.C1 U1.R20 | length 574.6
  Top Layer w15.75: v1(765,645) 765,715 798.35,748.35 798.35,816.7 U1.R20
  Bottom Layer w15.75: v1(765,645) 765.57,645.57 990.43,645.57 1017,619 C7.1
  Bottom Layer w19.68: SIM1.C1 944.32,566 C7.1@1015,566
pads on no net: ANT2.2 ANT2.3 ANT2.4 D1.2 U4.1 U4.5

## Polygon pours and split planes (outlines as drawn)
GND on L2 "G" (solid, remove dead copper, pour order 10): -74,1046 2606,1046 2628,1024 2658,994 2658,922 2658,10 2608,-40 2570,-78 2442,-78 24,-78 -78,24
GND on Top Layer "G" (solid, remove dead copper, pour order 12): -64,1086 2554,1086 2612,1028 2642,998 2642,912 2642,20 2580,-42 2534,-88 2362,-88 -4,-88 -60,-32
GND on L3 "G" (solid, remove dead copper, pour order 14): -83,1048 2599,1048 2606,1041 2638,1009 2638,900 2638,21 2587,-30 2545,-72 2380,-72 24,-72 -60,12
GND on Bottom Layer "G" (solid, remove dead copper, pour order 16): -67,1028 2631,1028 2669,990 2700,959 2700,625 2700,56 2628,-16 2580,-64 2232,-64 -49,-64 -60,-53

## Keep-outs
Keep-Out Layer:
  lines w3.94: -20.55,0 0,0 ; -0.28,171.52 -0.28,801.45 ; 0,-22.93 0,0 ; 0,22.93 0,0 ; 0,898.45 cw(c78.74,899.16) 63.62,976.44 ; 0,902.45 0,77.45 ccw(c78.73,78.45) 71.66,0.03 ; 63.61,976.5 329.42,976.5 372.39,976.5 ; 71.66,0 313.69,0 ; 312.12,0 1985.31,0 ; 320.57,0 321.96,0 323.61,0 ; 366.28,976.5 2032.04,976.5 ; 1957.8,0 2429.75,0 ; 2016.8,976.5 2429.64,976.5 2429.75,976.61 ; 2425.75,976.61 cw(c2426.46,897.87) 2504.73,906.45 ; 2427.03,-0.04 ccw(c2426.03,78.69) 2504.76,79.4 ; 2504.76,77.45 2504.76,906.45 ; 2504.8,171.52 2504.8,801.45 ; 0,0 20.55,0 0,0
  text ".Layer_Name" at -7,1074 h78.74

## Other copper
Top Layer:
  rectangle net +5V: 464.62,712.44 548.62,816
  rectangle net GND: 2323.7,293.57 2370.94,317.19
  rectangle net VDD33: 1387.12,862.44 1438.12,909.44
  rectangle net VDD33: 1396.12,779.44 1427.12,864.44
  rectangle net VDD1V8: 1319.12,837.44 1346.62,905.94
  rectangle net +5V: 489.12,762.44 537.12,858.44
  rectangle net RF_POWER: 14,541 91,580
  region net GND: 1868.77,770.39 1868.77,782 1874,782 1874,771 1872,771
  region net GND: 1309.38,830.75 1309.38,868.38 1292,868.38 1292,837
  region net GND: 1388,770.66 1388,784 1387,785 1383,781 1376,781 1376,770 1378,768
  pour cut-out: 1388,773 1388,749 1404,749 1404,770 1406,772
  region net GND: 775.26,789.05 775.26,771.49 778,768.75 778,765 771,765 766,770 766,781 765,782 765,787
  pour cut-out: 118.31,848.91 181.3,848.91 181.3,783.95 118.31,783.95
  pour cut-out: 72.29,249.12 125.66,249.12 125.66,193.78 72.29,193.78
  pour cut-out: 2613.18,482.9 2307.96,482.9 2307.96,1016.44 2614.18,1016.44 2614.18,903.58
  region net GND: 1358.66,858.83 1358.66,841.34 1362,838 1372,838 1372,863 1369,866
  region net RF_POWER: 91,580 83,588 83,598 80,598 60,578
  text ".Layer_Name" at -7,1074 h78.74
L2:
  pour cut-out: 118.31,848.91 181.3,848.91 181.3,783.95 118.31,783.95
  pour cut-out: 72.29,249.12 125.66,249.12 125.66,193.78 72.29,193.78
  pour cut-out: 2613.18,482.9 2307.96,482.9 2307.96,1016.44 2614.18,1016.44 2614.18,903.58
  text ".Layer_Name" at -7,1074 h78.74
L3:
  rectangle net RF_POWER: 1453.12,583.44 1482.12,635.44
  rectangle net VDD33: 562.12,853.44 618.12,910.44
  rectangle net +5V: 465.12,713.44 563.65,783.44
  rectangle net +5V: 1040,503.44 1111,597.44
  rectangle net VDD33: 1387.12,862.44 1438.12,909.44
  rectangle net VDD33: 1444.12,514.44 1502.12,571.44
  region net VDD33: 1358.12,844.44 1390.12,876.44 1397.12,869.44 1397.12,844.44
  region net VDD33: 1326.12,815.44 1360.12,815.44 1396.12,779.44 1406.12,789.44 1406.12,829.44
  region net VDD33: 1444.12,571.44 1430.12,585.44 1430.12,484.44 1426.12,480.44 1426.12,496.44 1448.12,518.44 1457.12,518.44
  region net RF_POWER: 1465.58,886.3 1465.58,905.3 1438.58,932.3 1443.58,937.3 1503.58,937.3 1473.58,907.3
  region net VDD33: 1438.12,862.44 1438.12,580.44 1454.12,564.44 1430.12,564.44 1424.12,570.44 1424.12,863.44 1434.12,873.44 1434.12,875.44
  pour cut-out: 118.31,848.91 181.3,848.91 181.3,783.95 118.31,783.95
  pour cut-out: 72.29,249.12 125.66,249.12 125.66,193.78 72.29,193.78
  pour cut-out: 2613.18,482.9 2307.96,482.9 2307.96,1016.44 2614.18,1016.44 2614.18,903.58
  text ".Layer_Name" at -7,1074 h78.74
Bottom Layer:
  rectangle net RF_POWER: 1428.12,580.44 1481.12,645.44
  rectangle net VDD33: 562.12,719.44 615.12,910.44
  rectangle net +5V: 369.43,718.44 545.12,777.44
  rectangle net +5V: 1057,499.44 1147.12,597.44
  rectangle net VDD5: 1156.12,510.44 1238.12,565.15
  rectangle net VDD33: 1427.12,461.44 1506.12,571.44
  rectangle net VDD5: 1184.12,560.44 1238.12,579.44
  rectangle net NetC26_1: 1229.12,474.44 1283.12,492.44
  rectangle net NetC26_1: 1120.12,362.44 1184.62,406.44
  rectangle net SW: 1120.12,432.44 1183.12,478.44
  rectangle net GND: 1197.12,412.44 1222.12,431.44
  rectangle net VDD1V8: 1400.12,627 1420.12,652.44
  pour cut-out: 720.62,816.8 734.2,816.8 735,816 735,823 730,828 715,828
  region net GND: 1156,581 1156,613 1163,606 1163,585
  region net GPIO21(6): 1705.87,154.93 1705.87,179.85 1737.29,211.27 1706.95,241.6 1703.05,241.6
  region net +5V: 401.12,722.44 431.12,742.44 433.12,742.44 433.12,773.44 403.12,803.44
  region net VDD5: 1202.12,499.44 1201.12,498.44 1198.12,498.44 1198.12,501 1181.12,518 1181.55,518.44 1235.12,518.44 1218.12,501.44
  region net NetC26_1: 1283.12,492.44 1290.12,492.44 1305.12,477.44 1305.12,424.44 1309.12,420.44 1324.12,420.44 1324.12,415.44 1327.12,412.44 1327.12,402.44 1320.12,395.44 1260.12,395.44 1283.12,418.44 1283.12,476.44 1275.12,484.44
  region net NetC26_1: 1180.62,362.44 1309.12,362.44 1328.12,381.44 1325.12,384.44 1170.12,384.44
  region net NetC26_1: 1298.12,433.44 1309.12,422.44 1495.12,422.44 1495.12,378.44 1295.12,378.44 1295.12,387.44
  region net SW: 1215.12,463.44 1188.12,463.44 1182.12,469.44 1176.12,463.44 1176.12,437.44 1193.12,454.44 1216.77,454.54
  region net SW: 1182.62,477.94 1182.62,472.94 1195.62,459.94 1200.62,459.94 1180.62,439.94 1176.62,443.94 1176.62,468.51
  region net VDD5: 1221.12,471.44 1210.12,471.44 1196.12,485.44 1196.12,503.44 1208.12,515.44 1222.12,515.44 1223.12,514.44 1221.12,512.44
  region net SW: 1183.12,478.44 1191.12,478.44 1206.12,463.44 1215.12,463.44 1184.12,432.44 1183.12,432.44 1176.12,439.44 1176.12,453.44
  region net GND: 1216.66,446.19 1210.37,446.19 1189.12,424.94 1189.12,416.44 1195.12,410.44 1229.62,410.44 1231.62,412.44 1231.62,424.94 1220.62,435.94 1220.62,443.94
  region net GND: 1231.62,424.94 1231.62,426.94 1219.62,438.94 1219.62,422.44 1221.62,420.44
  region net VDD5: 1269.12,463.44 1269.12,418.94 1252.94,418.94 1240.62,431.26 1240.62,463.44
  region net GND: 1231.62,426.76 1236.62,421.76 1236.62,410.44 1216.62,410.44 1216.62,417.94
  region net NetC26_1: 1229.12,492.11 1232.44,495.44 1294.12,495.44 1305.12,484.44 1305.12,477.44 1264.12,477.44 1263.12,478.44 1238.12,478.44
  region net NetR71_1: 1373.83,618.91 1403.06,618.91 1403.06,571.85 1418.18,571.85 1418.18,521.64 1373.83,521.64
  region net GPIO21(6): 2073.71,212.03 2095.03,233.35 2095.03,230.08 2111.87,213.24
  pour cut-out: 662.7,263.47 652.15,263.47 652.15,274.17 648.59,274.17 648.59,258.89 662.92,258.89
  pour cut-out: 118.31,848.91 181.3,848.91 181.3,783.95 118.31,783.95
  pour cut-out: 72.29,249.12 125.66,249.12 125.66,193.78 72.29,193.78
  pour cut-out: 2613.18,482.9 2307.96,482.9 2307.96,1016.44 2614.18,1016.44 2614.18,903.58
  region net GND: 1157.8,602.71 1156.59,604.52 1159,605
  text ".Layer_Name" at -7,1074 h78.74

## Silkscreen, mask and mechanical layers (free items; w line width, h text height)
Top Overlay:
  region: 2383.65,576.29 2469.72,576.29 2469.72,564.05 2383.19,564.05
  region: 2159.3,602.07 2157.78,604.6 2159.05,605.43 2160.57,605.52
  region: 2159.64,605.35 2162.67,604 2161.49,601.05 2158.72,601.56
  lines w3.94: 383.12,255.44 383.12,137.9 460.12,137.9 ; 383.12,749.44 383.12,832.9 484.73,832.9 ; 1028.12,832.78 1216.66,832.78 ; 1951.42,832.9 2063.12,832.9 2063.12,772.44 ; 1989.12,137.9 2063.12,137.9 2063.12,315.45 ; 2063.12,772.44 2063.12,772.44
  text ".Layer_Name" at -7,1074 h78.74
Bottom Overlay:
  drawing of 994 lines, arcs and shapes, not listed
  text "23" at 780.32,920.03 h59.06
  text "21" at 977.32,920.03 h59.06
  text "19" at 1166.32,920.03 h59.06
  text "17" at 1366.32,920.03 h59.06
  text "15" at 1575.32,920.03 h59.06
  text "13" at 1784.32,920.03 h59.06
  text "GND" at 634.22,918.45 h59.06
  text "3V3" at 666,780 h59.06 r90
  text "VIN" at 353,729 h59.06
  text "22" at 752.22,720.45 h59.06
  text "20" at 949.32,720.03 h59.06
  text "18" at 1157.32,720.03 h59.06
  text "16" at 1353.32,720.03 h59.06
  text "14" at 1554.32,720.03 h59.06
  text "COPYRIGHT  2017" at 2018,721 h59.06 r90
  text "Reference Board" at 1836,685 h59.06 r90
  text "The Netherlands" at 1945,681 h59.06 r90
  text "www.pycom.io" at 2074,660 h59.06 r90
  text "V2.0r" at 1893,589 h59.06 r90
  text "2" at 755.32,213.03 h59.06
  text "4" at 950.32,213.03 h59.06
  text "6" at 1148.32,213.03 h59.06
  text "8" at 1349.32,213.03 h59.06
  text "10" at 1575.32,213.03 h59.06
  text "12" at 1783.32,213.03 h59.06
  text "0" at 572,209 h59.06
  text "RST" at 349,26 h59.06
  text "1" at 544.32,22.03 h59.06
  text "3" at 748.32,22.03 h59.06
  text "5" at 952.32,22.03 h59.06
  text "7" at 1148.32,22.03 h59.06
  text "9" at 1350.32,22.03 h59.06
  text "11" at 1546.32,22.03 h59.06
Top Paste:
  text ".Layer_Name" at -7,1074 h78.74
Bottom Paste:
  text ".Layer_Name" at -7,1074 h78.74
Top Solder:
  text ".Layer_Name" at -7,1074 h78.74
Bottom Solder:
  text ".Layer_Name" at -7,1074 h78.74
Drill Guide:
  text ".Layer_Name" at -7,1074 h78.74
Mechanical 1:
  lines w3.94: 0,898.45 cw(c78.74,899.16) 63.62,976.44 ; 0,902.45 0,77.45 ccw(c78.73,78.45) 71.66,0.03 ; 63.61,976.5 329.42,976.5 372.39,976.5 ; 71.66,0 313.69,0 ; 312.12,0 1985.31,0 ; 366.28,976.5 2032.04,976.5 ; 1957.8,0 2429.75,0 ; 2016.8,976.5 2429.64,976.5 ; 2425.75,976.61 cw(c2426.46,897.87) 2504.73,906.45 ; 2427.03,-0.04 ccw(c2426.03,78.69) 2504.76,79.4 ; 2504.76,77.45 2504.76,906.45
  text ".Layer_Name" at -7,1154 h78.74
Drill Drawing:
  text ".Legend" at -7,1256 h78.74

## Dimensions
2429.64,976.5 to 2429.75,0 on Mechanical 1
0,899.16 to 2504.76,906.45 on Mechanical 1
